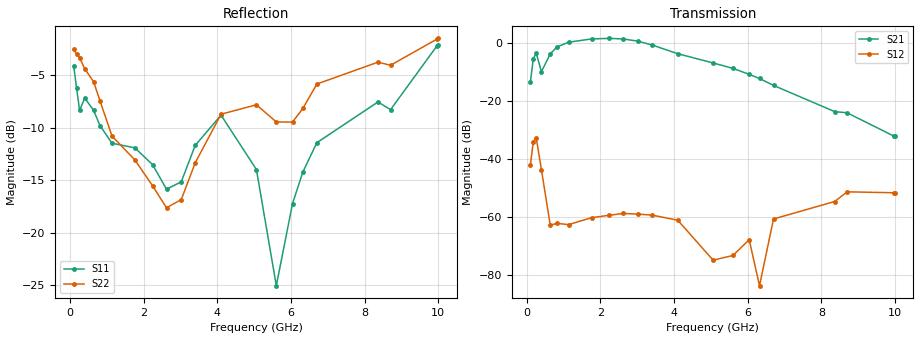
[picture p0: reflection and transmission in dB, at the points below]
! Integrated Device Technology
! Corporate Headquarters
! 6024 Silver Creek Valley Road
! San Jose, CA 95138  USA
! Phone:  1-408-284-8200
! Toll Free:  1-800-223-1366
! Webpage:  http://www.idt.com/
! Timing and RF Division
! 515 Groton Road, Suite 102
! Westford, MA 01886-6024
! Device:  F1456
! Description: 6-bit 0.5 dB Transmit Variable Gain Amplifier
! Frequency:  2100.0 -  2950.00 MHz
! Package:  6x6 mm Thin QFN Plastic Package: 28 pin
! State:  61
! Atten State:  30.5 dB
! Voltage:  +5.00 Volts
! Current:  216.914 mA
! Data:  The device was measured on a the F1455 evaluation board which has
!  individual transmission lines to the RF pins.  Data was collected
!  using a calibrated network analyzer.  The evaluation board was
!  de-embedded using a TRL calibration technique.
!  The reference plane is the edge of the package pin.
!  Pin  1 = CSb
!  Pin  2 = DATA
!  Pin  3 = CLK
!  Pin  4 = RSET
!  Pin  5 = GND
!  Pin  6 = RFIN  = Port 1
!  Pin  7 = GND
!  Pin  8 = NC
!  Pin  9 = NC
!  Pin 10 = NC
!  Pin 11 = NC
!  Pin 12 = NC
!  Pin 13 = NC
!  Pin 14 = /STBY
!  Pin 15 = GND
!  Pin 16 = RFOUT  = Port 2
!  Pin 17 = GND
!  Pin 18 = NC
!  Pin 19 = NC
!  Pin 20 = NC
!  Pin 21 = GND
!  Pin 22 = NC
!  Pin 23 = GND
!  Pin 24 = NC
!  Pin 25 = NC
!  Pin 26 = NC
!  Pin 27 = GND
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# GHz S dB R 50
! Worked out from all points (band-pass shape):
!   496 points, 100 MHz to 10 GHz, reference 50 ohm
!   highest |S21| = 1.45 dB at 2.24 GHz (marker M1); lowest = -32.2 dB at 9.96 GHz (marker M2)
!   |S21| within 3 dB of the highest: 813.5 MHz to 3.578 GHz (2.764 GHz wide, 126 % of centre)
!   lowest |S11| = -25.1 dB at 5.6 GHz (marker M3), VSWR 1.12, Z = 52.6 + j5.13 ohm
!   |S11| at or under -10 dB: 847.1 MHz to 3.657 GHz (2.81 GHz wide, 125 % of centre); 4.635 GHz to 7.072 GHz (2.437 GHz wide, 41.6 % of centre)
!   |S22| runs from -17.9 to -1.5 dB; largest |S21 - S12| = 1.2
!   S11 on the Smith chart (normalised r, x): 100 MHz: 2.37, -2.04; 640 MHz: 1.04, -0.84; 3.02 GHz: 0.76, +0.19; 6.04 GHz: 1.31, +0.08; 8.7 GHz: 0.89, +0.78; 10 GHz: 4.20, +4.18
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0.1  -4.10 -24.9  -13.73 -150.7  -42.31 50.4  -2.51 140.8
0.18  -6.23 -40.3  -5.52 159.3  -34.18 -2.4  -2.97 109.7
0.26  -8.33 -28.5  -3.67 60.3  -32.90 -100.8  -3.30 88.8
0.4  -7.16 -33.8  -10.02 -92.4  -43.78 149.6  -4.36 44.4
0.64  -8.33 -65.1  -3.92 109.3  -62.90 136.8  -5.60 -6.7
0.82  -9.82 -83.2  -1.50 57.8  -62.34 119.2  -7.48 -45.7
1.14  -11.47 -109.4  0.13 -2.0  -62.76 88.4  -10.79 -93.4
1.76  -11.91 -137.5  1.25 -84.6  -60.36 55.6  -13.06 -139.4
2.24  -13.51 -153.2  1.45 -138.7  -59.54 39.6  -15.53 -155.1
2.62  -15.86 -178.8  1.25 179.4  -58.91 26.9  -17.63 -170.3
3.02  -15.15 136.5  0.48 136.1  -59.12 9.8  -16.85 162.1
3.4  -11.67 114.5  -0.81 97.5  -59.48 -4.6  -13.33 142.3
4.1  -8.79 112.1  -3.84 36.9  -61.23 -38.8  -8.70 133.1
5.06  -13.98 119.8  -7.02 -37.6  -75.01 -79.5  -7.80 137.6
5.6  -25.07 60.6  -8.91 -83.4  -73.39 124.4  -9.44 123.4
6.04  -17.23 12.3  -10.94 -123.8  -67.96 115.4  -9.45 93.2
6.32  -14.22 20.3  -12.38 -149.5  -83.81 97.1  -8.15 76.3
6.7  -11.42 39.5  -14.77 175.3  -60.81 132.8  -5.82 64.4
8.36  -7.53 89.5  -23.80 57.9  -54.79 49.2  -3.73 62.4
8.7  -8.27 75.8  -24.22 30.5  -51.45 60.8  -4.03 51.2
9.96  -2.18 13.6  -32.20 -74.6  -51.77 -29.3  -1.53 -2.3
10  -2.06 13.8  -32.10 -75.4  -51.83 -31.5  -1.46 -2.6
